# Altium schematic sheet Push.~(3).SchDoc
size A4; SheetNumber: 1; SheetTotal: 1

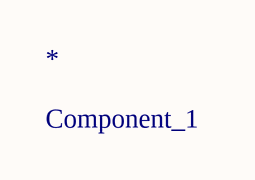
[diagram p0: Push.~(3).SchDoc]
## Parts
*  Component_1  [transformer]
